One B-rep face of a CAD part: STEP entity #137.
In plain terms, the planar face has unit normal (-1, 0, 0).
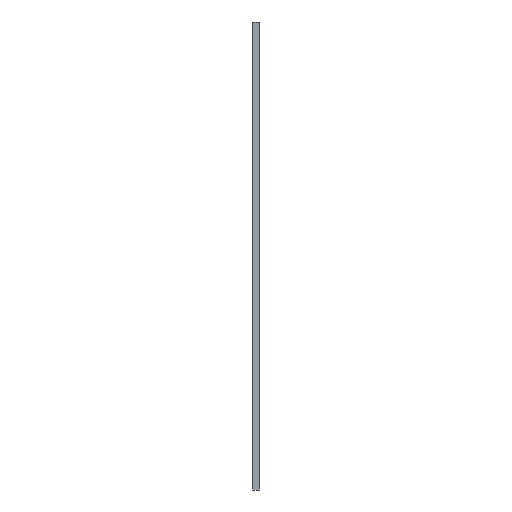
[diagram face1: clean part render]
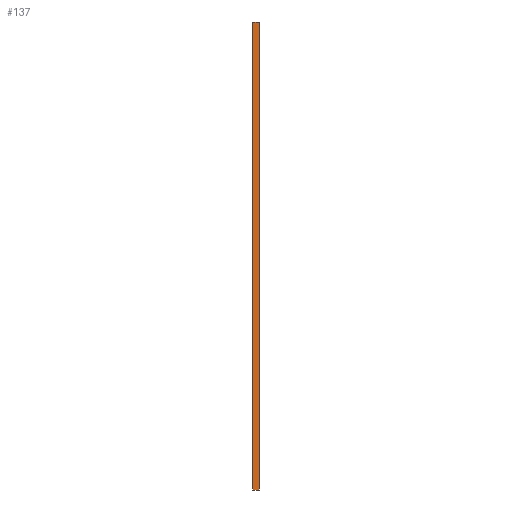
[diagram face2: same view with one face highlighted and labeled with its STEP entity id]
Its self-contained STEP definition (entity closure, numbers rounded to 3 decimals):
#21 = EDGE_CURVE('',#22,#24,#26,.T.);
#22 = VERTEX_POINT('',#23);
#23 = CARTESIAN_POINT('',(-110.,-2.,-136.));
#24 = VERTEX_POINT('',#25);
#25 = CARTESIAN_POINT('',(-110.,2.,-136.));
#26 = SURFACE_CURVE('',#27,(#31,#43),.PCURVE_S1.);
#27 = LINE('',#28,#29);
#28 = CARTESIAN_POINT('',(-110.,-2.,-136.));
#29 = VECTOR('',#30,1.);
#30 = DIRECTION('',(0.,1.,0.));
#31 = PCURVE('',#32,#37);
#32 = PLANE('',#33);
#33 = AXIS2_PLACEMENT_3D('',#34,#35,#36);
#34 = CARTESIAN_POINT('',(-110.,0.,-136.));
#35 = DIRECTION('',(-0.,0.,1.));
#36 = DIRECTION('',(1.,0.,0.));
#37 = DEFINITIONAL_REPRESENTATION('',(#38),#42);
#38 = LINE('',#39,#40);
#39 = CARTESIAN_POINT('',(0.,-2.));
#40 = VECTOR('',#41,1.);
#41 = DIRECTION('',(0.,1.));
#42 = ( GEOMETRIC_REPRESENTATION_CONTEXT(2) 
PARAMETRIC_REPRESENTATION_CONTEXT() REPRESENTATION_CONTEXT('2D SPACE',''
  ) );
#43 = PCURVE('',#44,#49);
#44 = PLANE('',#45);
#45 = AXIS2_PLACEMENT_3D('',#46,#47,#48);
#46 = CARTESIAN_POINT('',(-110.,0.,136.));
#47 = DIRECTION('',(1.,0.,0.));
#48 = DIRECTION('',(0.,0.,-1.));
#49 = DEFINITIONAL_REPRESENTATION('',(#50),#54);
#50 = LINE('',#51,#52);
#51 = CARTESIAN_POINT('',(272.,-2.));
#52 = VECTOR('',#53,1.);
#53 = DIRECTION('',(0.,1.));
#54 = ( GEOMETRIC_REPRESENTATION_CONTEXT(2) 
PARAMETRIC_REPRESENTATION_CONTEXT() REPRESENTATION_CONTEXT('2D SPACE',''
  ) );
#72 = PLANE('',#73);
#73 = AXIS2_PLACEMENT_3D('',#74,#75,#76);
#74 = CARTESIAN_POINT('',(3.139,-2.,0.));
#75 = DIRECTION('',(-0.,-1.,-0.));
#76 = DIRECTION('',(0.,0.,-1.));
#126 = PLANE('',#127);
#127 = AXIS2_PLACEMENT_3D('',#128,#129,#130);
#128 = CARTESIAN_POINT('',(3.139,2.,0.));
#129 = DIRECTION('',(-0.,-1.,-0.));
#130 = DIRECTION('',(0.,0.,-1.));
#137 = ADVANCED_FACE('',(#138),#44,.F.);
#138 = FACE_BOUND('',#139,.F.);
#139 = EDGE_LOOP('',(#140,#170,#191,#192));
#140 = ORIENTED_EDGE('',*,*,#141,.F.);
#141 = EDGE_CURVE('',#142,#144,#146,.T.);
#142 = VERTEX_POINT('',#143);
#143 = CARTESIAN_POINT('',(-110.,-2.,136.));
#144 = VERTEX_POINT('',#145);
#145 = CARTESIAN_POINT('',(-110.,2.,136.));
#146 = SURFACE_CURVE('',#147,(#151,#158),.PCURVE_S1.);
#147 = LINE('',#148,#149);
#148 = CARTESIAN_POINT('',(-110.,-2.,136.));
#149 = VECTOR('',#150,1.);
#150 = DIRECTION('',(0.,1.,0.));
#151 = PCURVE('',#44,#152);
#152 = DEFINITIONAL_REPRESENTATION('',(#153),#157);
#153 = LINE('',#154,#155);
#154 = CARTESIAN_POINT('',(0.,-2.));
#155 = VECTOR('',#156,1.);
#156 = DIRECTION('',(0.,1.));
#157 = ( GEOMETRIC_REPRESENTATION_CONTEXT(2) 
PARAMETRIC_REPRESENTATION_CONTEXT() REPRESENTATION_CONTEXT('2D SPACE',''
  ) );
#158 = PCURVE('',#159,#164);
#159 = PLANE('',#160);
#160 = AXIS2_PLACEMENT_3D('',#161,#162,#163);
#161 = CARTESIAN_POINT('',(78.,0.,136.));
#162 = DIRECTION('',(-0.,-0.,-1.));
#163 = DIRECTION('',(-1.,0.,0.));
#164 = DEFINITIONAL_REPRESENTATION('',(#165),#169);
#165 = LINE('',#166,#167);
#166 = CARTESIAN_POINT('',(188.,-2.));
#167 = VECTOR('',#168,1.);
#168 = DIRECTION('',(0.,1.));
#169 = ( GEOMETRIC_REPRESENTATION_CONTEXT(2) 
PARAMETRIC_REPRESENTATION_CONTEXT() REPRESENTATION_CONTEXT('2D SPACE',''
  ) );
#170 = ORIENTED_EDGE('',*,*,#171,.T.);
#171 = EDGE_CURVE('',#142,#22,#172,.T.);
#172 = SURFACE_CURVE('',#173,(#177,#184),.PCURVE_S1.);
#173 = LINE('',#174,#175);
#174 = CARTESIAN_POINT('',(-110.,-2.,136.));
#175 = VECTOR('',#176,1.);
#176 = DIRECTION('',(0.,0.,-1.));
#177 = PCURVE('',#44,#178);
#178 = DEFINITIONAL_REPRESENTATION('',(#179),#183);
#179 = LINE('',#180,#181);
#180 = CARTESIAN_POINT('',(0.,-2.));
#181 = VECTOR('',#182,1.);
#182 = DIRECTION('',(1.,0.));
#183 = ( GEOMETRIC_REPRESENTATION_CONTEXT(2) 
PARAMETRIC_REPRESENTATION_CONTEXT() REPRESENTATION_CONTEXT('2D SPACE',''
  ) );
#184 = PCURVE('',#72,#185);
#185 = DEFINITIONAL_REPRESENTATION('',(#186),#190);
#186 = LINE('',#187,#188);
#187 = CARTESIAN_POINT('',(-136.,-113.139));
#188 = VECTOR('',#189,1.);
#189 = DIRECTION('',(1.,0.));
#190 = ( GEOMETRIC_REPRESENTATION_CONTEXT(2) 
PARAMETRIC_REPRESENTATION_CONTEXT() REPRESENTATION_CONTEXT('2D SPACE',''
  ) );
#191 = ORIENTED_EDGE('',*,*,#21,.T.);
#192 = ORIENTED_EDGE('',*,*,#193,.F.);
#193 = EDGE_CURVE('',#144,#24,#194,.T.);
#194 = SURFACE_CURVE('',#195,(#199,#206),.PCURVE_S1.);
#195 = LINE('',#196,#197);
#196 = CARTESIAN_POINT('',(-110.,2.,136.));
#197 = VECTOR('',#198,1.);
#198 = DIRECTION('',(0.,0.,-1.));
#199 = PCURVE('',#44,#200);
#200 = DEFINITIONAL_REPRESENTATION('',(#201),#205);
#201 = LINE('',#202,#203);
#202 = CARTESIAN_POINT('',(0.,2.));
#203 = VECTOR('',#204,1.);
#204 = DIRECTION('',(1.,0.));
#205 = ( GEOMETRIC_REPRESENTATION_CONTEXT(2) 
PARAMETRIC_REPRESENTATION_CONTEXT() REPRESENTATION_CONTEXT('2D SPACE',''
  ) );
#206 = PCURVE('',#126,#207);
#207 = DEFINITIONAL_REPRESENTATION('',(#208),#212);
#208 = LINE('',#209,#210);
#209 = CARTESIAN_POINT('',(-136.,-113.139));
#210 = VECTOR('',#211,1.);
#211 = DIRECTION('',(1.,0.));
#212 = ( GEOMETRIC_REPRESENTATION_CONTEXT(2) 
PARAMETRIC_REPRESENTATION_CONTEXT() REPRESENTATION_CONTEXT('2D SPACE',''
  ) );
